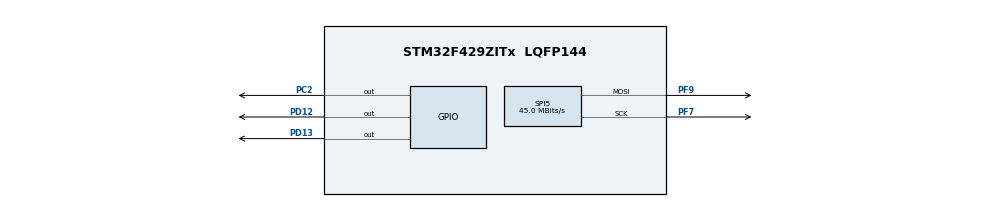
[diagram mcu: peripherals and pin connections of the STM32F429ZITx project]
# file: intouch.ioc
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Dma.Request0=SPI5_TX
Dma.SPI5_TX.0.Direction=DMA_MEMORY_TO_PERIPH
Dma.SPI5_TX.0.FIFOMode=DMA_FIFOMODE_DISABLE
Dma.SPI5_TX.0.Instance=DMA2_Stream4
Dma.SPI5_TX.0.MemDataAlignment=DMA_MDATAALIGN_BYTE
Dma.SPI5_TX.0.MemInc=DMA_MINC_ENABLE
Dma.SPI5_TX.0.Mode=DMA_NORMAL
Dma.SPI5_TX.0.PeriphDataAlignment=DMA_PDATAALIGN_BYTE
Dma.SPI5_TX.0.PeriphInc=DMA_PINC_DISABLE
Dma.SPI5_TX.0.Priority=DMA_PRIORITY_LOW
Mcu.Family=STM32F4
Mcu.Name=STM32F429ZITx
Mcu.Package=LQFP144
NVIC.DMA2_Stream4_IRQn=true\:0\:0\:false\:false\:true\:false\:true\:true
NVIC.PriorityGroup=NVIC_PRIORITYGROUP_4
PC2.Signal=GPIO_Output
PD12.Signal=GPIO_Output
PD13.Signal=GPIO_Output
PF7.Mode=TX_Only_Simplex_Unidirect_Master
PF7.Signal=SPI5_SCK
PF9.Mode=TX_Only_Simplex_Unidirect_Master
PF9.Signal=SPI5_MOSI
PH0/OSC_IN.Signal=RCC_OSC_IN
PH1/OSC_OUT.Signal=RCC_OSC_OUT
ProjectManager.HeapSize=0x200
ProjectManager.StackSize=0x400
ProjectManager.TargetToolchain=STM32CubeIDE
RCC.48MHZClocksFreq_Value=90000000
RCC.AHBFreq_Value=180000000
RCC.APB1CLKDivider=RCC_HCLK_DIV4
RCC.APB1Freq_Value=45000000
RCC.APB1TimFreq_Value=90000000
RCC.APB2CLKDivider=RCC_HCLK_DIV2
RCC.APB2Freq_Value=90000000
RCC.APB2TimFreq_Value=180000000
RCC.CortexFreq_Value=180000000
RCC.HCLKFreq_Value=180000000
RCC.HSE_VALUE=25000000
RCC.HSI_VALUE=16000000
RCC.LSE_VALUE=32768
RCC.PLLM=8
RCC.PLLN=180
RCC.SYSCLKFreq_VALUE=180000000
RCC.SYSCLKSource=RCC_SYSCLKSOURCE_PLLCLK
RCC.VCOOutputFreq_Value=360000000
SPI5.CalculateBaudRate=45.0 MBits/s
SPI5.Direction=SPI_DIRECTION_2LINES
SPI5.Mode=SPI_MODE_MASTER
SPI5.VirtualType=VM_MASTER
board=custom

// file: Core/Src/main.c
/* USER CODE BEGIN Header */
/**
  ******************************************************************************
  * @file           : main.c
  * @brief          : Main program body
  ******************************************************************************
  * @attention
  *
  * Copyright (c) 2025 STMicroelectronics.
  * All rights reserved.
  *
  * This software is licensed under terms that can be found in the LICENSE file
  * in the root directory of this software component.
  * If no LICENSE file comes with this software, it is provided AS-IS.
  *
  ******************************************************************************
  */
/* USER CODE END Header */
#include "main.h"

/* USER CODE BEGIN Includes */
#include "fonts.h"
#include "ILI9341_GFX.h"
#include "ILI9341_STM32_Driver.h"
#include <math.h>

/* USER CODE END Includes */

/* USER CODE BEGIN PD */
#define PI 3.14159265
/* USER CODE END PD */

SPI_HandleTypeDef hspi5;
DMA_HandleTypeDef hdma_spi5_tx;

void SystemClock_Config(void);
static void MX_GPIO_Init(void);
static void MX_DMA_Init(void);
static void MX_SPI5_Init(void);

/* USER CODE BEGIN 0 */
void swap_int(int *a, int *b) {
    int temp = *a;
    *a = *b;
    *b = temp;
}

void ILI9341_DrawFilledTriangle(int x0, int y0,
                                int x1, int y1,
                                int x2, int y2,
                                uint16_t color) {
    // Sort vertices by y-coordinate ascending (y0 <= y1 <= y2)
    if (y0 > y1) { swap_int(&y0, &y1); swap_int(&x0, &x1); }
    if (y1 > y2) { swap_int(&y2, &y1); swap_int(&x2, &x1); }
    if (y0 > y1) { swap_int(&y0, &y1); swap_int(&x0, &x1); }

    int total_height = y2 - y0;
    for (int i = 0; i < total_height; i++) {
        int second_half = i > y1 - y0 || y1 == y0;
        int segment_height = second_half ? y2 - y1 : y1 - y0;

        float alpha = (float)i / total_height;
        float beta = (float)(i - (second_half ? y1 - y0 : 0)) / segment_height;

        int ax = x0 + (x2 - x0) * alpha;
        int bx = second_half
                 ? x1 + (x2 - x1) * beta
                 : x0 + (x1 - x0) * beta;

        if (ax > bx) swap_int(&ax, &bx);
        for (int j = ax; j <= bx; j++) {
            ILI9341_DrawPixel(j, y0 + i, color);
        }
    }
}

void drawStar(int x, int y, int radius, uint16_t color) {
    float angle = PI / 2; // Start pointing upwards
    int points[10][2];

    // Calculate points for a 5-pointed star
    // Making the inner radius smaller will create a thinner star
    float innerRadiusRatio = 0.38; // Reduced from 0.5 to make star thinner

    for (int i = 0; i < 10; i++) {
        float r = (i % 2 == 0) ? radius : radius * innerRadiusRatio;
        points[i][0] = x + r * cos(angle);
        points[i][1] = y - r * sin(angle);
        angle += PI / 5;
    }

    // Draw the star using triangles from the center point
    for (int i = 0; i < 10; i++) {
        int next = (i + 1) % 10;
        ILI9341_DrawFilledTriangle(
            x, y,                      // Center of star
            points[i][0], points[i][1], // Current point
            points[next][0], points[next][1], // Next point
            color
        );
    }
}
/* USER CODE END 0 */

int main(void)
{

  /* MCU Configuration--------------------------------------------------------*/

  /* Reset of all peripherals, Initializes the Flash interface and the Systick. */
  HAL_Init();

  /* Configure the system clock */
  SystemClock_Config();

  /* Initialize all configured peripherals */
  MX_GPIO_Init();
  MX_DMA_Init();
  MX_SPI5_Init();
  /* USER CODE BEGIN 2 */
  ILI9341_Init();

  ILI9341_FillScreen(RED);
  ILI9341_SetRotation(SCREEN_HORIZONTAL_2);

  // Draw background elements first
//  ILI9341_DrawFilledCircle(160, 120, 70, RED);
  drawStar(160, 120, 80, YELLOW);

  // Draw text last so it appears on top
  //ILI9341_DrawText("VietNam", FONT4, 90, 200, BLACK, WHITE);

//  drawStar(160, 120, 50, YELLOW);
  HAL_Delay(1000);
  /* USER CODE END 2 */

  /* Infinite loop */
  while (1)
  {

  }
}

void SystemClock_Config(void)
{
  RCC_OscInitTypeDef RCC_OscInitStruct = {0};
  RCC_ClkInitTypeDef RCC_ClkInitStruct = {0};

  /** Configure the main internal regulator output voltage
  */
  __HAL_RCC_PWR_CLK_ENABLE();
  __HAL_PWR_VOLTAGESCALING_CONFIG(PWR_REGULATOR_VOLTAGE_SCALE1);

  /** Initializes the RCC Oscillators according to the specified parameters
  * in the RCC_OscInitTypeDef structure.
  */
  RCC_OscInitStruct.OscillatorType = RCC_OSCILLATORTYPE_HSE;
  RCC_OscInitStruct.HSEState = RCC_HSE_ON;
  RCC_OscInitStruct.PLL.PLLState = RCC_PLL_ON;
  RCC_OscInitStruct.PLL.PLLSource = RCC_PLLSOURCE_HSE;
  RCC_OscInitStruct.PLL.PLLM = 4;
  RCC_OscInitStruct.PLL.PLLN = 180;
  RCC_OscInitStruct.PLL.PLLP = RCC_PLLP_DIV2;
  RCC_OscInitStruct.PLL.PLLQ = 4;
  if (HAL_RCC_OscConfig(&RCC_OscInitStruct) != HAL_OK)
  {
    Error_Handler();
  }

  /** Activate the Over-Drive mode
  */
  if (HAL_PWREx_EnableOverDrive() != HAL_OK)
  {
    Error_Handler();
  }

  /** Initializes the CPU, AHB and APB buses clocks
  */
  RCC_ClkInitStruct.ClockType = RCC_CLOCKTYPE_HCLK|RCC_CLOCKTYPE_SYSCLK
                              |RCC_CLOCKTYPE_PCLK1|RCC_CLOCKTYPE_PCLK2;
  RCC_ClkInitStruct.SYSCLKSource = RCC_SYSCLKSOURCE_PLLCLK;
  RCC_ClkInitStruct.AHBCLKDivider = RCC_SYSCLK_DIV1;
  RCC_ClkInitStruct.APB1CLKDivider = RCC_HCLK_DIV4;
  RCC_ClkInitStruct.APB2CLKDivider = RCC_HCLK_DIV4;

  if (HAL_RCC_ClockConfig(&RCC_ClkInitStruct, FLASH_LATENCY_5) != HAL_OK)
  {
    Error_Handler();
  }
}

static void MX_SPI5_Init(void)
{

  /* SPI5 parameter configuration*/
  hspi5.Instance = SPI5;
  hspi5.Init.Mode = SPI_MODE_MASTER;
  hspi5.Init.Direction = SPI_DIRECTION_2LINES;
  hspi5.Init.DataSize = SPI_DATASIZE_8BIT;
  hspi5.Init.CLKPolarity = SPI_POLARITY_LOW;
  hspi5.Init.CLKPhase = SPI_PHASE_1EDGE;
  hspi5.Init.NSS = SPI_NSS_SOFT;
  hspi5.Init.BaudRatePrescaler = SPI_BAUDRATEPRESCALER_2;
  hspi5.Init.FirstBit = SPI_FIRSTBIT_MSB;
  hspi5.Init.TIMode = SPI_TIMODE_DISABLE;
  hspi5.Init.CRCCalculation = SPI_CRCCALCULATION_DISABLE;
  hspi5.Init.CRCPolynomial = 10;
  if (HAL_SPI_Init(&hspi5) != HAL_OK)
  {
    Error_Handler();
  }

}

static void MX_DMA_Init(void)
{

  /* DMA controller clock enable */
  __HAL_RCC_DMA2_CLK_ENABLE();

  /* DMA interrupt init */
  /* DMA2_Stream4_IRQn interrupt configuration */
  HAL_NVIC_SetPriority(DMA2_Stream4_IRQn, 0, 0);
  HAL_NVIC_EnableIRQ(DMA2_Stream4_IRQn);

}

static void MX_GPIO_Init(void)
{
  GPIO_InitTypeDef GPIO_InitStruct = {0};

  /* GPIO Ports Clock Enable */
  __HAL_RCC_GPIOF_CLK_ENABLE();
  __HAL_RCC_GPIOH_CLK_ENABLE();
  __HAL_RCC_GPIOC_CLK_ENABLE();
  __HAL_RCC_GPIOD_CLK_ENABLE();
  __HAL_RCC_GPIOG_CLK_ENABLE();

  /*Configure GPIO pin Output Level */
  HAL_GPIO_WritePin(GPIOC, GPIO_PIN_2, GPIO_PIN_RESET);

  /*Configure GPIO pin Output Level */
  HAL_GPIO_WritePin(GPIOD, GPIO_PIN_12|GPIO_PIN_13, GPIO_PIN_RESET);

  /*Configure GPIO pin Output Level */
  HAL_GPIO_WritePin(GPIOG, GPIO_PIN_13|GPIO_PIN_14, GPIO_PIN_RESET);

  /*Configure GPIO pin : PC2 */
  GPIO_InitStruct.Pin = GPIO_PIN_2;
  GPIO_InitStruct.Mode = GPIO_MODE_OUTPUT_PP;
  GPIO_InitStruct.Pull = GPIO_NOPULL;
  GPIO_InitStruct.Speed = GPIO_SPEED_FREQ_LOW;
  HAL_GPIO_Init(GPIOC, &GPIO_InitStruct);

  /*Configure GPIO pins : PD12 PD13 */
  GPIO_InitStruct.Pin = GPIO_PIN_12|GPIO_PIN_13;
  GPIO_InitStruct.Mode = GPIO_MODE_OUTPUT_PP;
  GPIO_InitStruct.Pull = GPIO_NOPULL;
  GPIO_InitStruct.Speed = GPIO_SPEED_FREQ_LOW;
  HAL_GPIO_Init(GPIOD, &GPIO_InitStruct);

  /*Configure GPIO pins : PG13 PG14 */
  GPIO_InitStruct.Pin = GPIO_PIN_13|GPIO_PIN_14;
  GPIO_InitStruct.Mode = GPIO_MODE_OUTPUT_PP;
  GPIO_InitStruct.Pull = GPIO_NOPULL;
  GPIO_InitStruct.Speed = GPIO_SPEED_FREQ_LOW;
  HAL_GPIO_Init(GPIOG, &GPIO_InitStruct);

}

void Error_Handler(void)
{
  __disable_irq();
  while (1)
  {
  }
}
